VERSION 5.7 ;
BUSBITCHARS "[]" ;
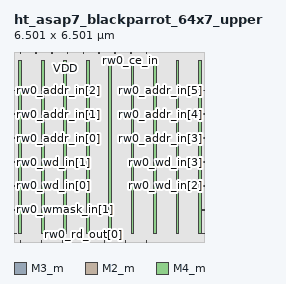
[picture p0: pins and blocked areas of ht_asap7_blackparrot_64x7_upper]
MACRO ht_asap7_blackparrot_64x7_upper
  FOREIGN ht_asap7_blackparrot_64x7_upper 0 0 ;
  SYMMETRY X Y R90 ;
  SIZE 6.501 BY 6.501 ;
  CLASS BLOCK ;
  PIN rw0_wmask_in[0]
    DIRECTION INPUT ;
    USE SIGNAL ;
    SHAPE ABUTMENT ;
    PORT
      LAYER M3_m ;
      RECT 0.000 0.276 0.072 0.300 ;
    END
  END rw0_wmask_in[0]
  PIN rw0_wmask_in[1]
    DIRECTION INPUT ;
    USE SIGNAL ;
    SHAPE ABUTMENT ;
    PORT
      LAYER M3_m ;
      RECT 0.000 1.092 0.072 1.116 ;
    END
  END rw0_wmask_in[1]
  PIN rw0_wmask_in[2]
    DIRECTION INPUT ;
    USE SIGNAL ;
    SHAPE ABUTMENT ;
    PORT
      LAYER M3_m ;
      RECT 6.429 0.276 6.501 0.300 ;
    END
  END rw0_wmask_in[2]
  PIN rw0_wmask_in[3]
    DIRECTION INPUT ;
    USE SIGNAL ;
    SHAPE ABUTMENT ;
    PORT
      LAYER M3_m ;
      RECT 6.429 1.092 6.501 1.116 ;
    END
  END rw0_wmask_in[3]
  PIN rw0_wmask_in[4]
    DIRECTION INPUT ;
    USE SIGNAL ;
    SHAPE ABUTMENT ;
    PORT
      LAYER M2_m ;
      RECT 0.207 6.447 0.225 6.501 ;
    END
  END rw0_wmask_in[4]
  PIN rw0_wmask_in[5]
    DIRECTION INPUT ;
    USE SIGNAL ;
    SHAPE ABUTMENT ;
    PORT
      LAYER M2_m ;
      RECT 0.747 6.447 0.765 6.501 ;
    END
  END rw0_wmask_in[5]
  PIN rw0_wmask_in[6]
    DIRECTION INPUT ;
    USE SIGNAL ;
    SHAPE ABUTMENT ;
    PORT
      LAYER M2_m ;
      RECT 1.287 6.447 1.305 6.501 ;
    END
  END rw0_wmask_in[6]
  PIN rw0_wd_in[0]
    DIRECTION INPUT ;
    USE SIGNAL ;
    SHAPE ABUTMENT ;
    PORT
      LAYER M3_m ;
      RECT 0.000 1.908 0.072 1.932 ;
    END
  END rw0_wd_in[0]
  PIN rw0_wd_in[1]
    DIRECTION INPUT ;
    USE SIGNAL ;
    SHAPE ABUTMENT ;
    PORT
      LAYER M3_m ;
      RECT 0.000 2.724 0.072 2.748 ;
    END
  END rw0_wd_in[1]
  PIN rw0_wd_in[2]
    DIRECTION INPUT ;
    USE SIGNAL ;
    SHAPE ABUTMENT ;
    PORT
      LAYER M3_m ;
      RECT 6.429 1.908 6.501 1.932 ;
    END
  END rw0_wd_in[2]
  PIN rw0_wd_in[3]
    DIRECTION INPUT ;
    USE SIGNAL ;
    SHAPE ABUTMENT ;
    PORT
      LAYER M3_m ;
      RECT 6.429 2.724 6.501 2.748 ;
    END
  END rw0_wd_in[3]
  PIN rw0_wd_in[4]
    DIRECTION INPUT ;
    USE SIGNAL ;
    SHAPE ABUTMENT ;
    PORT
      LAYER M2_m ;
      RECT 0.207 0.000 0.225 0.054 ;
    END
  END rw0_wd_in[4]
  PIN rw0_wd_in[5]
    DIRECTION INPUT ;
    USE SIGNAL ;
    SHAPE ABUTMENT ;
    PORT
      LAYER M2_m ;
      RECT 0.927 0.000 0.945 0.054 ;
    END
  END rw0_wd_in[5]
  PIN rw0_wd_in[6]
    DIRECTION INPUT ;
    USE SIGNAL ;
    SHAPE ABUTMENT ;
    PORT
      LAYER M2_m ;
      RECT 1.647 0.000 1.665 0.054 ;
    END
  END rw0_wd_in[6]
  PIN rw0_rd_out[0]
    DIRECTION OUTPUT ;
    USE SIGNAL ;
    SHAPE ABUTMENT ;
    PORT
      LAYER M2_m ;
      RECT 2.367 0.000 2.385 0.054 ;
    END
  END rw0_rd_out[0]
  PIN rw0_rd_out[1]
    DIRECTION OUTPUT ;
    USE SIGNAL ;
    SHAPE ABUTMENT ;
    PORT
      LAYER M2_m ;
      RECT 3.087 0.000 3.105 0.054 ;
    END
  END rw0_rd_out[1]
  PIN rw0_rd_out[2]
    DIRECTION OUTPUT ;
    USE SIGNAL ;
    SHAPE ABUTMENT ;
    PORT
      LAYER M2_m ;
      RECT 3.807 0.000 3.825 0.054 ;
    END
  END rw0_rd_out[2]
  PIN rw0_rd_out[3]
    DIRECTION OUTPUT ;
    USE SIGNAL ;
    SHAPE ABUTMENT ;
    PORT
      LAYER M2_m ;
      RECT 4.527 0.000 4.545 0.054 ;
    END
  END rw0_rd_out[3]
  PIN rw0_rd_out[4]
    DIRECTION OUTPUT ;
    USE SIGNAL ;
    SHAPE ABUTMENT ;
    PORT
      LAYER M2_m ;
      RECT 1.827 6.447 1.845 6.501 ;
    END
  END rw0_rd_out[4]
  PIN rw0_rd_out[5]
    DIRECTION OUTPUT ;
    USE SIGNAL ;
    SHAPE ABUTMENT ;
    PORT
      LAYER M2_m ;
      RECT 2.367 6.447 2.385 6.501 ;
    END
  END rw0_rd_out[5]
  PIN rw0_rd_out[6]
    DIRECTION OUTPUT ;
    USE SIGNAL ;
    SHAPE ABUTMENT ;
    PORT
      LAYER M2_m ;
      RECT 2.907 6.447 2.925 6.501 ;
    END
  END rw0_rd_out[6]
  PIN rw0_addr_in[0]
    DIRECTION INPUT ;
    USE SIGNAL ;
    SHAPE ABUTMENT ;
    PORT
      LAYER M3_m ;
      RECT 0.000 3.540 0.072 3.564 ;
    END
  END rw0_addr_in[0]
  PIN rw0_addr_in[1]
    DIRECTION INPUT ;
    USE SIGNAL ;
    SHAPE ABUTMENT ;
    PORT
      LAYER M3_m ;
      RECT 0.000 4.356 0.072 4.380 ;
    END
  END rw0_addr_in[1]
  PIN rw0_addr_in[2]
    DIRECTION INPUT ;
    USE SIGNAL ;
    SHAPE ABUTMENT ;
    PORT
      LAYER M3_m ;
      RECT 0.000 5.172 0.072 5.196 ;
    END
  END rw0_addr_in[2]
  PIN rw0_addr_in[3]
    DIRECTION INPUT ;
    USE SIGNAL ;
    SHAPE ABUTMENT ;
    PORT
      LAYER M3_m ;
      RECT 6.429 3.540 6.501 3.564 ;
    END
  END rw0_addr_in[3]
  PIN rw0_addr_in[4]
    DIRECTION INPUT ;
    USE SIGNAL ;
    SHAPE ABUTMENT ;
    PORT
      LAYER M3_m ;
      RECT 6.429 4.356 6.501 4.380 ;
    END
  END rw0_addr_in[4]
  PIN rw0_addr_in[5]
    DIRECTION INPUT ;
    USE SIGNAL ;
    SHAPE ABUTMENT ;
    PORT
      LAYER M3_m ;
      RECT 6.429 5.172 6.501 5.196 ;
    END
  END rw0_addr_in[5]
  PIN rw0_we_in
    DIRECTION INPUT ;
    USE SIGNAL ;
    SHAPE ABUTMENT ;
    PORT
      LAYER M2_m ;
      RECT 3.447 6.447 3.465 6.501 ;
    END
  END rw0_we_in
  PIN rw0_ce_in
    DIRECTION INPUT ;
    USE SIGNAL ;
    SHAPE ABUTMENT ;
    PORT
      LAYER M2_m ;
      RECT 3.987 6.447 4.005 6.501 ;
    END
  END rw0_ce_in
  PIN rw0_clk
    DIRECTION INPUT ;
    USE SIGNAL ;
    SHAPE ABUTMENT ;
    PORT
      LAYER M2_m ;
      RECT 4.527 6.447 4.545 6.501 ;
    END
  END rw0_clk
  PIN VSS
    DIRECTION INOUT ;
    USE GROUND ;
    PORT
      LAYER M4_m ;
      RECT 0.168 0.288 0.264 6.213 ;
      RECT 0.936 0.288 1.032 6.213 ;
      RECT 1.704 0.288 1.800 6.213 ;
      RECT 2.472 0.288 2.568 6.213 ;
      RECT 3.240 0.288 3.336 6.213 ;
      RECT 4.008 0.288 4.104 6.213 ;
      RECT 4.776 0.288 4.872 6.213 ;
      RECT 5.544 0.288 5.640 6.213 ;
      RECT 6.312 0.288 6.408 6.213 ;
    END
  END VSS
  PIN VDD
    DIRECTION INOUT ;
    USE POWER ;
    PORT
      LAYER M4_m ;
      RECT 0.168 0.288 0.264 6.213 ;
      RECT 0.936 0.288 1.032 6.213 ;
      RECT 1.704 0.288 1.800 6.213 ;
      RECT 2.472 0.288 2.568 6.213 ;
      RECT 3.240 0.288 3.336 6.213 ;
      RECT 4.008 0.288 4.104 6.213 ;
      RECT 4.776 0.288 4.872 6.213 ;
      RECT 5.544 0.288 5.640 6.213 ;
      RECT 6.312 0.288 6.408 6.213 ;
    END
  END VDD
  OBS
    LAYER M1_m ;
    RECT 0 0 6.501 6.501 ;
    LAYER M2_m ;
    RECT 0 0 6.501 6.501 ;
    LAYER M3_m ;
    RECT 0 0 6.501 6.501 ;
    LAYER M4_m ;
    RECT 0 0 6.501 6.501 ;
  END
END ht_asap7_blackparrot_64x7_upper

END LIBRARY
